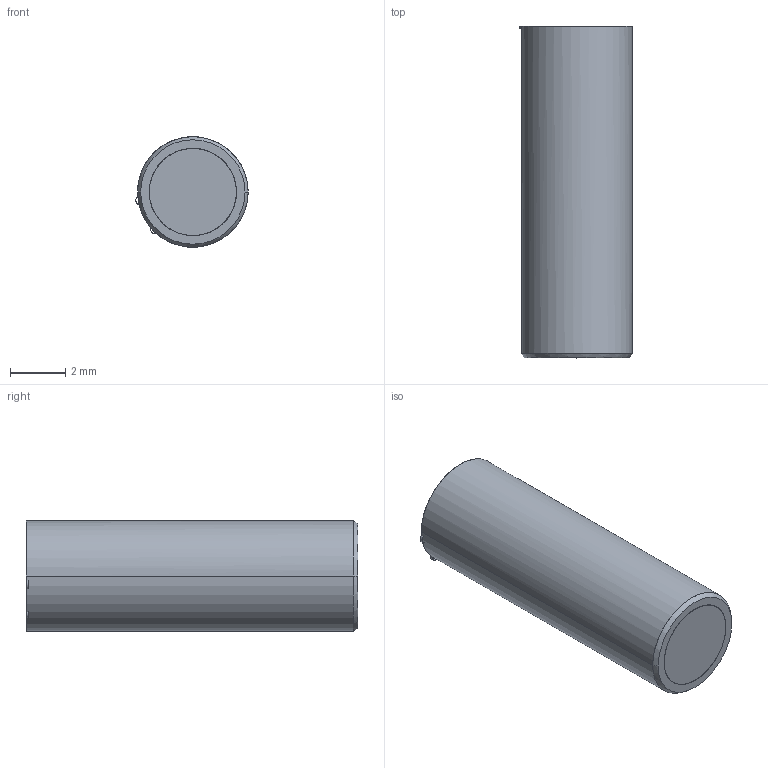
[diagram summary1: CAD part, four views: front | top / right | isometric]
IGES file: header records copied from the file, then geometry measured from it (millimetres).
Start section: START RECORD GO HERE.
Global section: file name: fa0422sf.igs; native system: DASSAULT SYSTEMES CATIA V5 R20 - www.3ds.com; preprocessor: CATIA Version 5 Release 20 ; author: Utente; organization: NB04-ASUS; date: 20201108.084211; units: millimetre
Bounding box: 4.06 x 12 x 4 mm (x, y, z)
Surface area: 504.6 mm2 (no closed solid volume)
Topology: 0 solids, 0 shells, 503 faces, 2324 edges, 2318 vertices
Faces by surface type: bspline 216, revolution 163, plane 124
